VERSION 5.7 ;
  NOWIREEXTENSIONATPIN ON ;
  DIVIDERCHAR "/" ;
  BUSBITCHARS "[]" ;
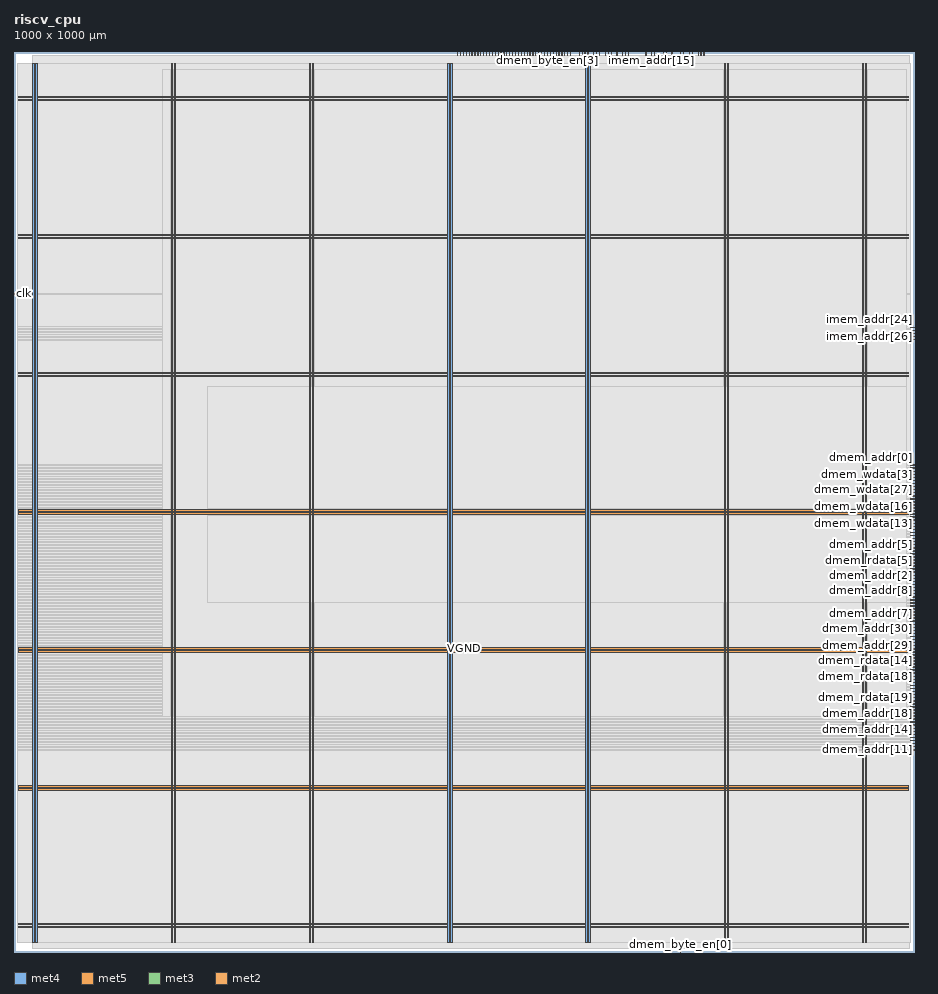
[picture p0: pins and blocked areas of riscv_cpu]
MACRO riscv_cpu
  CLASS BLOCK ;
  FOREIGN riscv_cpu ;
  ORIGIN 0.000 0.000 ;
  SIZE 1000.000 BY 1000.000 ;
  PIN VGND
    DIRECTION INOUT ;
    USE GROUND ;
    PORT
      LAYER met4 ;
        RECT 24.340 10.640 25.940 987.600 ;
    END
    PORT
      LAYER met4 ;
        RECT 177.940 10.640 179.540 987.600 ;
    END
    PORT
      LAYER met4 ;
        RECT 331.540 10.640 333.140 987.600 ;
    END
    PORT
      LAYER met4 ;
        RECT 485.140 10.640 486.740 987.600 ;
    END
    PORT
      LAYER met4 ;
        RECT 638.740 10.640 640.340 987.600 ;
    END
    PORT
      LAYER met4 ;
        RECT 792.340 10.640 793.940 987.600 ;
    END
    PORT
      LAYER met4 ;
        RECT 945.940 10.640 947.540 987.600 ;
    END
    PORT
      LAYER met5 ;
        RECT 5.280 30.030 994.300 31.630 ;
    END
    PORT
      LAYER met5 ;
        RECT 5.280 183.210 994.300 184.810 ;
    END
    PORT
      LAYER met5 ;
        RECT 5.280 336.390 994.300 337.990 ;
    END
    PORT
      LAYER met5 ;
        RECT 5.280 489.570 994.300 491.170 ;
    END
    PORT
      LAYER met5 ;
        RECT 5.280 642.750 994.300 644.350 ;
    END
    PORT
      LAYER met5 ;
        RECT 5.280 795.930 994.300 797.530 ;
    END
    PORT
      LAYER met5 ;
        RECT 5.280 949.110 994.300 950.710 ;
    END
  END VGND
  PIN VPWR
    DIRECTION INOUT ;
    USE POWER ;
    PORT
      LAYER met4 ;
        RECT 21.040 10.640 22.640 987.600 ;
    END
    PORT
      LAYER met4 ;
        RECT 174.640 10.640 176.240 987.600 ;
    END
    PORT
      LAYER met4 ;
        RECT 328.240 10.640 329.840 987.600 ;
    END
    PORT
      LAYER met4 ;
        RECT 481.840 10.640 483.440 987.600 ;
    END
    PORT
      LAYER met4 ;
        RECT 635.440 10.640 637.040 987.600 ;
    END
    PORT
      LAYER met4 ;
        RECT 789.040 10.640 790.640 987.600 ;
    END
    PORT
      LAYER met4 ;
        RECT 942.640 10.640 944.240 987.600 ;
    END
    PORT
      LAYER met5 ;
        RECT 5.280 26.730 994.300 28.330 ;
    END
    PORT
      LAYER met5 ;
        RECT 5.280 179.910 994.300 181.510 ;
    END
    PORT
      LAYER met5 ;
        RECT 5.280 333.090 994.300 334.690 ;
    END
    PORT
      LAYER met5 ;
        RECT 5.280 486.270 994.300 487.870 ;
    END
    PORT
      LAYER met5 ;
        RECT 5.280 639.450 994.300 641.050 ;
    END
    PORT
      LAYER met5 ;
        RECT 5.280 792.630 994.300 794.230 ;
    END
    PORT
      LAYER met5 ;
        RECT 5.280 945.810 994.300 947.410 ;
    END
  END VPWR
  PIN clk
    DIRECTION INPUT ;
    USE SIGNAL ;
    ANTENNAGATEAREA 0.852000 ;
    PORT
      LAYER met3 ;
        RECT 0.000 731.040 4.000 731.640 ;
    END
  END clk
  PIN dmem_addr[0]
    DIRECTION OUTPUT TRISTATE ;
    USE SIGNAL ;
    ANTENNADIFFAREA 0.445500 ;
    PORT
      LAYER met3 ;
        RECT 996.000 540.640 1000.000 541.240 ;
    END
  END dmem_addr[0]
  PIN dmem_addr[10]
    DIRECTION OUTPUT TRISTATE ;
    USE SIGNAL ;
    ANTENNADIFFAREA 0.445500 ;
    PORT
      LAYER met3 ;
        RECT 996.000 360.440 1000.000 361.040 ;
    END
  END dmem_addr[10]
  PIN dmem_addr[11]
    DIRECTION OUTPUT TRISTATE ;
    USE SIGNAL ;
    ANTENNADIFFAREA 0.795200 ;
    PORT
      LAYER met3 ;
        RECT 996.000 224.440 1000.000 225.040 ;
    END
  END dmem_addr[11]
  PIN dmem_addr[12]
    DIRECTION OUTPUT TRISTATE ;
    USE SIGNAL ;
    ANTENNADIFFAREA 0.445500 ;
    PORT
      LAYER met3 ;
        RECT 996.000 346.840 1000.000 347.440 ;
    END
  END dmem_addr[12]
  PIN dmem_addr[13]
    DIRECTION OUTPUT TRISTATE ;
    USE SIGNAL ;
    ANTENNADIFFAREA 0.795200 ;
    PORT
      LAYER met3 ;
        RECT 996.000 227.840 1000.000 228.440 ;
    END
  END dmem_addr[13]
  PIN dmem_addr[14]
    DIRECTION OUTPUT TRISTATE ;
    USE SIGNAL ;
    ANTENNADIFFAREA 0.445500 ;
    PORT
      LAYER met3 ;
        RECT 996.000 238.040 1000.000 238.640 ;
    END
  END dmem_addr[14]
  PIN dmem_addr[15]
    DIRECTION OUTPUT TRISTATE ;
    USE SIGNAL ;
    ANTENNADIFFAREA 0.795200 ;
    PORT
      LAYER met3 ;
        RECT 996.000 241.440 1000.000 242.040 ;
    END
  END dmem_addr[15]
  PIN dmem_addr[16]
    DIRECTION OUTPUT TRISTATE ;
    USE SIGNAL ;
    ANTENNADIFFAREA 0.795200 ;
    PORT
      LAYER met3 ;
        RECT 996.000 336.640 1000.000 337.240 ;
    END
  END dmem_addr[16]
  PIN dmem_addr[17]
    DIRECTION OUTPUT TRISTATE ;
    USE SIGNAL ;
    ANTENNADIFFAREA 0.445500 ;
    PORT
      LAYER met3 ;
        RECT 996.000 251.640 1000.000 252.240 ;
    END
  END dmem_addr[17]
  PIN dmem_addr[18]
    DIRECTION OUTPUT TRISTATE ;
    USE SIGNAL ;
    ANTENNADIFFAREA 0.445500 ;
    PORT
      LAYER met3 ;
        RECT 996.000 265.240 1000.000 265.840 ;
    END
  END dmem_addr[18]
  PIN dmem_addr[19]
    DIRECTION OUTPUT TRISTATE ;
    USE SIGNAL ;
    ANTENNADIFFAREA 0.795200 ;
    PORT
      LAYER met3 ;
        RECT 996.000 275.440 1000.000 276.040 ;
    END
  END dmem_addr[19]
  PIN dmem_addr[1]
    DIRECTION OUTPUT TRISTATE ;
    USE SIGNAL ;
    ANTENNADIFFAREA 0.445500 ;
    PORT
      LAYER met3 ;
        RECT 996.000 445.440 1000.000 446.040 ;
    END
  END dmem_addr[1]
  PIN dmem_addr[20]
    DIRECTION OUTPUT TRISTATE ;
    USE SIGNAL ;
    ANTENNADIFFAREA 0.795200 ;
    PORT
      LAYER met3 ;
        RECT 996.000 302.640 1000.000 303.240 ;
    END
  END dmem_addr[20]
  PIN dmem_addr[21]
    DIRECTION OUTPUT TRISTATE ;
    USE SIGNAL ;
    ANTENNADIFFAREA 0.795200 ;
    PORT
      LAYER met3 ;
        RECT 996.000 255.040 1000.000 255.640 ;
    END
  END dmem_addr[21]
  PIN dmem_addr[22]
    DIRECTION OUTPUT TRISTATE ;
    USE SIGNAL ;
    ANTENNADIFFAREA 0.445500 ;
    PORT
      LAYER met3 ;
        RECT 996.000 278.840 1000.000 279.440 ;
    END
  END dmem_addr[22]
  PIN dmem_addr[23]
    DIRECTION OUTPUT TRISTATE ;
    USE SIGNAL ;
    ANTENNADIFFAREA 0.795200 ;
    PORT
      LAYER met3 ;
        RECT 996.000 268.640 1000.000 269.240 ;
    END
  END dmem_addr[23]
  PIN dmem_addr[24]
    DIRECTION OUTPUT TRISTATE ;
    USE SIGNAL ;
    ANTENNADIFFAREA 0.445500 ;
    PORT
      LAYER met3 ;
        RECT 996.000 312.840 1000.000 313.440 ;
    END
  END dmem_addr[24]
  PIN dmem_addr[25]
    DIRECTION OUTPUT TRISTATE ;
    USE SIGNAL ;
    ANTENNADIFFAREA 0.445500 ;
    PORT
      LAYER met3 ;
        RECT 996.000 319.640 1000.000 320.240 ;
    END
  END dmem_addr[25]
  PIN dmem_addr[26]
    DIRECTION OUTPUT TRISTATE ;
    USE SIGNAL ;
    ANTENNADIFFAREA 0.795200 ;
    PORT
      LAYER met3 ;
        RECT 996.000 248.240 1000.000 248.840 ;
    END
  END dmem_addr[26]
  PIN dmem_addr[27]
    DIRECTION OUTPUT TRISTATE ;
    USE SIGNAL ;
    ANTENNADIFFAREA 0.445500 ;
    PORT
      LAYER met3 ;
        RECT 996.000 343.440 1000.000 344.040 ;
    END
  END dmem_addr[27]
  PIN dmem_addr[28]
    DIRECTION OUTPUT TRISTATE ;
    USE SIGNAL ;
    ANTENNADIFFAREA 0.795200 ;
    PORT
      LAYER met3 ;
        RECT 996.000 234.640 1000.000 235.240 ;
    END
  END dmem_addr[28]
  PIN dmem_addr[29]
    DIRECTION OUTPUT TRISTATE ;
    USE SIGNAL ;
    ANTENNADIFFAREA 0.445500 ;
    PORT
      LAYER met3 ;
        RECT 996.000 340.040 1000.000 340.640 ;
    END
  END dmem_addr[29]
  PIN dmem_addr[2]
    DIRECTION OUTPUT TRISTATE ;
    USE SIGNAL ;
    ANTENNADIFFAREA 0.445500 ;
    PORT
      LAYER met3 ;
        RECT 996.000 418.240 1000.000 418.840 ;
    END
  END dmem_addr[2]
  PIN dmem_addr[30]
    DIRECTION OUTPUT TRISTATE ;
    USE SIGNAL ;
    ANTENNADIFFAREA 0.795200 ;
    PORT
      LAYER met3 ;
        RECT 996.000 350.240 1000.000 350.840 ;
    END
  END dmem_addr[30]
  PIN dmem_addr[31]
    DIRECTION OUTPUT TRISTATE ;
    USE SIGNAL ;
    ANTENNADIFFAREA 0.445500 ;
    PORT
      LAYER met3 ;
        RECT 996.000 370.640 1000.000 371.240 ;
    END
  END dmem_addr[31]
  PIN dmem_addr[3]
    DIRECTION OUTPUT TRISTATE ;
    USE SIGNAL ;
    ANTENNADIFFAREA 0.445500 ;
    PORT
      LAYER met3 ;
        RECT 996.000 520.240 1000.000 520.840 ;
    END
  END dmem_addr[3]
  PIN dmem_addr[4]
    DIRECTION OUTPUT TRISTATE ;
    USE SIGNAL ;
    ANTENNADIFFAREA 0.795200 ;
    PORT
      LAYER met3 ;
        RECT 996.000 428.440 1000.000 429.040 ;
    END
  END dmem_addr[4]
  PIN dmem_addr[5]
    DIRECTION OUTPUT TRISTATE ;
    USE SIGNAL ;
    ANTENNADIFFAREA 0.445500 ;
    PORT
      LAYER met3 ;
        RECT 996.000 452.240 1000.000 452.840 ;
    END
  END dmem_addr[5]
  PIN dmem_addr[6]
    DIRECTION OUTPUT TRISTATE ;
    USE SIGNAL ;
    ANTENNADIFFAREA 0.795200 ;
    PORT
      LAYER met3 ;
        RECT 996.000 357.040 1000.000 357.640 ;
    END
  END dmem_addr[6]
  PIN dmem_addr[7]
    DIRECTION OUTPUT TRISTATE ;
    USE SIGNAL ;
    ANTENNADIFFAREA 0.445500 ;
    PORT
      LAYER met3 ;
        RECT 996.000 367.240 1000.000 367.840 ;
    END
  END dmem_addr[7]
  PIN dmem_addr[8]
    DIRECTION OUTPUT TRISTATE ;
    USE SIGNAL ;
    ANTENNADIFFAREA 0.445500 ;
    PORT
      LAYER met3 ;
        RECT 996.000 401.240 1000.000 401.840 ;
    END
  END dmem_addr[8]
  PIN dmem_addr[9]
    DIRECTION OUTPUT TRISTATE ;
    USE SIGNAL ;
    ANTENNADIFFAREA 0.795200 ;
    PORT
      LAYER met3 ;
        RECT 996.000 380.840 1000.000 381.440 ;
    END
  END dmem_addr[9]
  PIN dmem_byte_en[0]
    DIRECTION OUTPUT TRISTATE ;
    USE SIGNAL ;
    PORT
      LAYER met2 ;
        RECT 740.690 0.000 740.970 4.000 ;
    END
  END dmem_byte_en[0]
  PIN dmem_byte_en[1]
    DIRECTION OUTPUT TRISTATE ;
    USE SIGNAL ;
    ANTENNADIFFAREA 0.795200 ;
    PORT
      LAYER met2 ;
        RECT 608.670 996.000 608.950 1000.000 ;
    END
  END dmem_byte_en[1]
  PIN dmem_byte_en[2]
    DIRECTION OUTPUT TRISTATE ;
    USE SIGNAL ;
    ANTENNADIFFAREA 0.795200 ;
    PORT
      LAYER met2 ;
        RECT 582.910 996.000 583.190 1000.000 ;
    END
  END dmem_byte_en[2]
  PIN dmem_byte_en[3]
    DIRECTION OUTPUT TRISTATE ;
    USE SIGNAL ;
    ANTENNADIFFAREA 0.795200 ;
    PORT
      LAYER met2 ;
        RECT 592.570 996.000 592.850 1000.000 ;
    END
  END dmem_byte_en[3]
  PIN dmem_rdata[0]
    DIRECTION INPUT ;
    USE SIGNAL ;
    ANTENNAGATEAREA 0.213000 ;
    PORT
      LAYER met3 ;
        RECT 996.000 462.440 1000.000 463.040 ;
    END
  END dmem_rdata[0]
  PIN dmem_rdata[10]
    DIRECTION INPUT ;
    USE SIGNAL ;
    ANTENNAGATEAREA 0.213000 ;
    PORT
      LAYER met3 ;
        RECT 996.000 374.040 1000.000 374.640 ;
    END
  END dmem_rdata[10]
  PIN dmem_rdata[11]
    DIRECTION INPUT ;
    USE SIGNAL ;
    ANTENNAGATEAREA 0.213000 ;
    PORT
      LAYER met3 ;
        RECT 996.000 363.840 1000.000 364.440 ;
    END
  END dmem_rdata[11]
  PIN dmem_rdata[12]
    DIRECTION INPUT ;
    USE SIGNAL ;
    ANTENNAGATEAREA 0.213000 ;
    PORT
      LAYER met3 ;
        RECT 996.000 353.640 1000.000 354.240 ;
    END
  END dmem_rdata[12]
  PIN dmem_rdata[13]
    DIRECTION INPUT ;
    USE SIGNAL ;
    ANTENNAGATEAREA 0.213000 ;
    PORT
      LAYER met3 ;
        RECT 996.000 261.840 1000.000 262.440 ;
    END
  END dmem_rdata[13]
  PIN dmem_rdata[14]
    DIRECTION INPUT ;
    USE SIGNAL ;
    ANTENNAGATEAREA 0.213000 ;
    PORT
      LAYER met3 ;
        RECT 996.000 323.040 1000.000 323.640 ;
    END
  END dmem_rdata[14]
  PIN dmem_rdata[15]
    DIRECTION INPUT ;
    USE SIGNAL ;
    ANTENNAGATEAREA 0.213000 ;
    PORT
      LAYER met3 ;
        RECT 996.000 309.440 1000.000 310.040 ;
    END
  END dmem_rdata[15]
  PIN dmem_rdata[16]
    DIRECTION INPUT ;
    USE SIGNAL ;
    ANTENNAGATEAREA 0.213000 ;
    PORT
      LAYER met3 ;
        RECT 996.000 244.840 1000.000 245.440 ;
    END
  END dmem_rdata[16]
  PIN dmem_rdata[17]
    DIRECTION INPUT ;
    USE SIGNAL ;
    ANTENNAGATEAREA 0.213000 ;
    PORT
      LAYER met3 ;
        RECT 996.000 272.040 1000.000 272.640 ;
    END
  END dmem_rdata[17]
  PIN dmem_rdata[18]
    DIRECTION INPUT ;
    USE SIGNAL ;
    ANTENNAGATEAREA 0.213000 ;
    PORT
      LAYER met3 ;
        RECT 996.000 306.040 1000.000 306.640 ;
    END
  END dmem_rdata[18]
  PIN dmem_rdata[19]
    DIRECTION INPUT ;
    USE SIGNAL ;
    ANTENNAGATEAREA 0.159000 ;
    PORT
      LAYER met3 ;
        RECT 996.000 282.240 1000.000 282.840 ;
    END
  END dmem_rdata[19]
  PIN dmem_rdata[1]
    DIRECTION INPUT ;
    USE SIGNAL ;
    ANTENNAGATEAREA 0.213000 ;
    PORT
      LAYER met3 ;
        RECT 996.000 421.640 1000.000 422.240 ;
    END
  END dmem_rdata[1]
  PIN dmem_rdata[20]
    DIRECTION INPUT ;
    USE SIGNAL ;
    ANTENNAGATEAREA 0.213000 ;
    PORT
      LAYER met3 ;
        RECT 996.000 285.640 1000.000 286.240 ;
    END
  END dmem_rdata[20]
  PIN dmem_rdata[21]
    DIRECTION INPUT ;
    USE SIGNAL ;
    ANTENNAGATEAREA 0.159000 ;
    PORT
      LAYER met3 ;
        RECT 996.000 299.240 1000.000 299.840 ;
    END
  END dmem_rdata[21]
  PIN dmem_rdata[22]
    DIRECTION INPUT ;
    USE SIGNAL ;
    ANTENNAGATEAREA 0.159000 ;
    PORT
      LAYER met3 ;
        RECT 996.000 292.440 1000.000 293.040 ;
    END
  END dmem_rdata[22]
  PIN dmem_rdata[23]
    DIRECTION INPUT ;
    USE SIGNAL ;
    ANTENNAGATEAREA 0.213000 ;
    PORT
      LAYER met3 ;
        RECT 996.000 289.040 1000.000 289.640 ;
    END
  END dmem_rdata[23]
  PIN dmem_rdata[24]
    DIRECTION INPUT ;
    USE SIGNAL ;
    ANTENNAGATEAREA 0.213000 ;
    PORT
      LAYER met3 ;
        RECT 996.000 295.840 1000.000 296.440 ;
    END
  END dmem_rdata[24]
  PIN dmem_rdata[25]
    DIRECTION INPUT ;
    USE SIGNAL ;
    ANTENNAGATEAREA 0.213000 ;
    PORT
      LAYER met3 ;
        RECT 996.000 316.240 1000.000 316.840 ;
    END
  END dmem_rdata[25]
  PIN dmem_rdata[26]
    DIRECTION INPUT ;
    USE SIGNAL ;
    ANTENNAGATEAREA 0.213000 ;
    PORT
      LAYER met3 ;
        RECT 996.000 258.440 1000.000 259.040 ;
    END
  END dmem_rdata[26]
  PIN dmem_rdata[27]
    DIRECTION INPUT ;
    USE SIGNAL ;
    ANTENNAGATEAREA 0.213000 ;
    PORT
      LAYER met3 ;
        RECT 996.000 333.240 1000.000 333.840 ;
    END
  END dmem_rdata[27]
  PIN dmem_rdata[28]
    DIRECTION INPUT ;
    USE SIGNAL ;
    ANTENNAGATEAREA 0.213000 ;
    PORT
      LAYER met3 ;
        RECT 996.000 326.440 1000.000 327.040 ;
    END
  END dmem_rdata[28]
  PIN dmem_rdata[29]
    DIRECTION INPUT ;
    USE SIGNAL ;
    ANTENNAGATEAREA 0.213000 ;
    PORT
      LAYER met3 ;
        RECT 996.000 231.240 1000.000 231.840 ;
    END
  END dmem_rdata[29]
  PIN dmem_rdata[2]
    DIRECTION INPUT ;
    USE SIGNAL ;
    ANTENNAGATEAREA 0.213000 ;
    PORT
      LAYER met3 ;
        RECT 996.000 425.040 1000.000 425.640 ;
    END
  END dmem_rdata[2]
  PIN dmem_rdata[30]
    DIRECTION INPUT ;
    USE SIGNAL ;
    ANTENNAGATEAREA 0.213000 ;
    PORT
      LAYER met3 ;
        RECT 996.000 329.840 1000.000 330.440 ;
    END
  END dmem_rdata[30]
  PIN dmem_rdata[31]
    DIRECTION INPUT ;
    USE SIGNAL ;
    ANTENNAGATEAREA 0.213000 ;
    PORT
      LAYER met3 ;
        RECT 996.000 459.040 1000.000 459.640 ;
    END
  END dmem_rdata[31]
  PIN dmem_rdata[3]
    DIRECTION INPUT ;
    USE SIGNAL ;
    ANTENNAGATEAREA 0.213000 ;
    PORT
      LAYER met3 ;
        RECT 996.000 438.640 1000.000 439.240 ;
    END
  END dmem_rdata[3]
  PIN dmem_rdata[4]
    DIRECTION INPUT ;
    USE SIGNAL ;
    ANTENNAGATEAREA 0.213000 ;
    PORT
      LAYER met3 ;
        RECT 996.000 506.640 1000.000 507.240 ;
    END
  END dmem_rdata[4]
  PIN dmem_rdata[5]
    DIRECTION INPUT ;
    USE SIGNAL ;
    ANTENNAGATEAREA 0.213000 ;
    PORT
      LAYER met3 ;
        RECT 996.000 435.240 1000.000 435.840 ;
    END
  END dmem_rdata[5]
  PIN dmem_rdata[6]
    DIRECTION INPUT ;
    USE SIGNAL ;
    ANTENNAGATEAREA 0.213000 ;
    PORT
      LAYER met3 ;
        RECT 996.000 411.440 1000.000 412.040 ;
    END
  END dmem_rdata[6]
  PIN dmem_rdata[7]
    DIRECTION INPUT ;
    USE SIGNAL ;
    ANTENNAGATEAREA 0.213000 ;
    PORT
      LAYER met3 ;
        RECT 996.000 377.440 1000.000 378.040 ;
    END
  END dmem_rdata[7]
  PIN dmem_rdata[8]
    DIRECTION INPUT ;
    USE SIGNAL ;
    ANTENNAGATEAREA 0.213000 ;
    PORT
      LAYER met3 ;
        RECT 996.000 387.640 1000.000 388.240 ;
    END
  END dmem_rdata[8]
  PIN dmem_rdata[9]
    DIRECTION INPUT ;
    USE SIGNAL ;
    ANTENNAGATEAREA 0.213000 ;
    PORT
      LAYER met3 ;
        RECT 996.000 384.240 1000.000 384.840 ;
    END
  END dmem_rdata[9]
  PIN dmem_re
    DIRECTION OUTPUT TRISTATE ;
    USE SIGNAL ;
    ANTENNADIFFAREA 0.795200 ;
    PORT
      LAYER met2 ;
        RECT 566.810 996.000 567.090 1000.000 ;
    END
  END dmem_re
  PIN dmem_wdata[0]
    DIRECTION OUTPUT TRISTATE ;
    USE SIGNAL ;
    ANTENNADIFFAREA 0.795200 ;
    PORT
      LAYER met3 ;
        RECT 996.000 516.840 1000.000 517.440 ;
    END
  END dmem_wdata[0]
  PIN dmem_wdata[10]
    DIRECTION OUTPUT TRISTATE ;
    USE SIGNAL ;
    ANTENNADIFFAREA 0.795200 ;
    PORT
      LAYER met3 ;
        RECT 996.000 408.040 1000.000 408.640 ;
    END
  END dmem_wdata[10]
  PIN dmem_wdata[11]
    DIRECTION OUTPUT TRISTATE ;
    USE SIGNAL ;
    ANTENNADIFFAREA 0.445500 ;
    PORT
      LAYER met3 ;
        RECT 996.000 472.640 1000.000 473.240 ;
    END
  END dmem_wdata[11]
  PIN dmem_wdata[12]
    DIRECTION OUTPUT TRISTATE ;
    USE SIGNAL ;
    ANTENNADIFFAREA 0.445500 ;
    PORT
      LAYER met3 ;
        RECT 996.000 391.040 1000.000 391.640 ;
    END
  END dmem_wdata[12]
  PIN dmem_wdata[13]
    DIRECTION OUTPUT TRISTATE ;
    USE SIGNAL ;
    ANTENNADIFFAREA 0.795200 ;
    PORT
      LAYER met3 ;
        RECT 996.000 476.040 1000.000 476.640 ;
    END
  END dmem_wdata[13]
  PIN dmem_wdata[14]
    DIRECTION OUTPUT TRISTATE ;
    USE SIGNAL ;
    ANTENNADIFFAREA 0.795200 ;
    PORT
      LAYER met3 ;
        RECT 996.000 404.640 1000.000 405.240 ;
    END
  END dmem_wdata[14]
  PIN dmem_wdata[15]
    DIRECTION OUTPUT TRISTATE ;
    USE SIGNAL ;
    ANTENNADIFFAREA 0.445500 ;
    PORT
      LAYER met3 ;
        RECT 996.000 394.440 1000.000 395.040 ;
    END
  END dmem_wdata[15]
  PIN dmem_wdata[16]
    DIRECTION OUTPUT TRISTATE ;
    USE SIGNAL ;
    ANTENNADIFFAREA 0.445500 ;
    PORT
      LAYER met3 ;
        RECT 996.000 486.240 1000.000 486.840 ;
    END
  END dmem_wdata[16]
  PIN dmem_wdata[17]
    DIRECTION OUTPUT TRISTATE ;
    USE SIGNAL ;
    ANTENNADIFFAREA 0.445500 ;
    PORT
      LAYER met3 ;
        RECT 996.000 527.040 1000.000 527.640 ;
    END
  END dmem_wdata[17]
  PIN dmem_wdata[18]
    DIRECTION OUTPUT TRISTATE ;
    USE SIGNAL ;
    ANTENNADIFFAREA 0.795200 ;
    PORT
      LAYER met3 ;
        RECT 996.000 455.640 1000.000 456.240 ;
    END
  END dmem_wdata[18]
  PIN dmem_wdata[19]
    DIRECTION OUTPUT TRISTATE ;
    USE SIGNAL ;
    ANTENNADIFFAREA 0.795200 ;
    PORT
      LAYER met3 ;
        RECT 996.000 510.040 1000.000 510.640 ;
    END
  END dmem_wdata[19]
  PIN dmem_wdata[1]
    DIRECTION OUTPUT TRISTATE ;
    USE SIGNAL ;
    ANTENNADIFFAREA 0.795200 ;
    PORT
      LAYER met3 ;
        RECT 996.000 496.440 1000.000 497.040 ;
    END
  END dmem_wdata[1]
  PIN dmem_wdata[20]
    DIRECTION OUTPUT TRISTATE ;
    USE SIGNAL ;
    ANTENNADIFFAREA 0.795200 ;
    PORT
      LAYER met3 ;
        RECT 996.000 448.840 1000.000 449.440 ;
    END
  END dmem_wdata[20]
  PIN dmem_wdata[21]
    DIRECTION OUTPUT TRISTATE ;
    USE SIGNAL ;
    ANTENNADIFFAREA 0.795200 ;
    PORT
      LAYER met3 ;
        RECT 996.000 482.840 1000.000 483.440 ;
    END
  END dmem_wdata[21]
  PIN dmem_wdata[22]
    DIRECTION OUTPUT TRISTATE ;
    USE SIGNAL ;
    ANTENNADIFFAREA 0.445500 ;
    PORT
      LAYER met3 ;
        RECT 996.000 499.840 1000.000 500.440 ;
    END
  END dmem_wdata[22]
  PIN dmem_wdata[23]
    DIRECTION OUTPUT TRISTATE ;
    USE SIGNAL ;
    ANTENNADIFFAREA 0.445500 ;
    PORT
      LAYER met3 ;
        RECT 996.000 465.840 1000.000 466.440 ;
    END
  END dmem_wdata[23]
  PIN dmem_wdata[24]
    DIRECTION OUTPUT TRISTATE ;
    USE SIGNAL ;
    ANTENNADIFFAREA 0.445500 ;
    PORT
      LAYER met3 ;
        RECT 996.000 442.040 1000.000 442.640 ;
    END
  END dmem_wdata[24]
  PIN dmem_wdata[25]
    DIRECTION OUTPUT TRISTATE ;
    USE SIGNAL ;
    ANTENNADIFFAREA 0.445500 ;
    PORT
      LAYER met3 ;
        RECT 996.000 469.240 1000.000 469.840 ;
    END
  END dmem_wdata[25]
  PIN dmem_wdata[26]
    DIRECTION OUTPUT TRISTATE ;
    USE SIGNAL ;
    ANTENNADIFFAREA 0.795200 ;
    PORT
      LAYER met3 ;
        RECT 996.000 537.240 1000.000 537.840 ;
    END
  END dmem_wdata[26]
  PIN dmem_wdata[27]
    DIRECTION OUTPUT TRISTATE ;
    USE SIGNAL ;
    ANTENNADIFFAREA 0.445500 ;
    PORT
      LAYER met3 ;
        RECT 996.000 513.440 1000.000 514.040 ;
    END
  END dmem_wdata[27]
  PIN dmem_wdata[28]
    DIRECTION OUTPUT TRISTATE ;
    USE SIGNAL ;
    ANTENNADIFFAREA 0.445500 ;
    PORT
      LAYER met3 ;
        RECT 996.000 493.040 1000.000 493.640 ;
    END
  END dmem_wdata[28]
  PIN dmem_wdata[29]
    DIRECTION OUTPUT TRISTATE ;
    USE SIGNAL ;
    ANTENNADIFFAREA 0.795200 ;
    PORT
      LAYER met3 ;
        RECT 996.000 489.640 1000.000 490.240 ;
    END
  END dmem_wdata[29]
  PIN dmem_wdata[2]
    DIRECTION OUTPUT TRISTATE ;
    USE SIGNAL ;
    ANTENNADIFFAREA 0.445500 ;
    PORT
      LAYER met3 ;
        RECT 996.000 479.440 1000.000 480.040 ;
    END
  END dmem_wdata[2]
  PIN dmem_wdata[30]
    DIRECTION OUTPUT TRISTATE ;
    USE SIGNAL ;
    ANTENNADIFFAREA 0.795200 ;
    PORT
      LAYER met3 ;
        RECT 996.000 523.640 1000.000 524.240 ;
    END
  END dmem_wdata[30]
  PIN dmem_wdata[31]
    DIRECTION OUTPUT TRISTATE ;
    USE SIGNAL ;
    ANTENNADIFFAREA 0.445500 ;
    PORT
      LAYER met3 ;
        RECT 996.000 533.840 1000.000 534.440 ;
    END
  END dmem_wdata[31]
  PIN dmem_wdata[3]
    DIRECTION OUTPUT TRISTATE ;
    USE SIGNAL ;
    ANTENNADIFFAREA 0.795200 ;
    PORT
      LAYER met3 ;
        RECT 996.000 530.440 1000.000 531.040 ;
    END
  END dmem_wdata[3]
  PIN dmem_wdata[4]
    DIRECTION OUTPUT TRISTATE ;
    USE SIGNAL ;
    ANTENNADIFFAREA 0.445500 ;
    PORT
      LAYER met3 ;
        RECT 996.000 414.840 1000.000 415.440 ;
    END
  END dmem_wdata[4]
  PIN dmem_wdata[5]
    DIRECTION OUTPUT TRISTATE ;
    USE SIGNAL ;
    ANTENNADIFFAREA 0.795200 ;
    PORT
      LAYER met2 ;
        RECT 615.110 996.000 615.390 1000.000 ;
    END
  END dmem_wdata[5]
  PIN dmem_wdata[6]
    DIRECTION OUTPUT TRISTATE ;
    USE SIGNAL ;
    ANTENNADIFFAREA 0.795200 ;
    PORT
      LAYER met2 ;
        RECT 611.890 996.000 612.170 1000.000 ;
    END
  END dmem_wdata[6]
  PIN dmem_wdata[7]
    DIRECTION OUTPUT TRISTATE ;
    USE SIGNAL ;
    ANTENNADIFFAREA 0.795200 ;
    PORT
      LAYER met2 ;
        RECT 618.330 996.000 618.610 1000.000 ;
    END
  END dmem_wdata[7]
  PIN dmem_wdata[8]
    DIRECTION OUTPUT TRISTATE ;
    USE SIGNAL ;
    ANTENNADIFFAREA 0.445500 ;
    PORT
      LAYER met3 ;
        RECT 996.000 397.840 1000.000 398.440 ;
    END
  END dmem_wdata[8]
  PIN dmem_wdata[9]
    DIRECTION OUTPUT TRISTATE ;
    USE SIGNAL ;
    ANTENNADIFFAREA 0.795200 ;
    PORT
      LAYER met3 ;
        RECT 996.000 503.240 1000.000 503.840 ;
    END
  END dmem_wdata[9]
  PIN dmem_we
    DIRECTION OUTPUT TRISTATE ;
    USE SIGNAL ;
    ANTENNADIFFAREA 0.795200 ;
    PORT
      LAYER met2 ;
        RECT 586.130 996.000 586.410 1000.000 ;
    END
  END dmem_we
  PIN imem_addr[0]
    DIRECTION OUTPUT TRISTATE ;
    USE SIGNAL ;
    ANTENNADIFFAREA 0.795200 ;
    PORT
      LAYER met2 ;
        RECT 656.970 996.000 657.250 1000.000 ;
    END
  END imem_addr[0]
  PIN imem_addr[10]
    DIRECTION OUTPUT TRISTATE ;
    USE SIGNAL ;
    ANTENNADIFFAREA 0.795200 ;
    PORT
      LAYER met2 ;
        RECT 663.410 996.000 663.690 1000.000 ;
    END
  END imem_addr[10]
  PIN imem_addr[11]
    DIRECTION OUTPUT TRISTATE ;
    USE SIGNAL ;
    ANTENNADIFFAREA 0.795200 ;
    PORT
      LAYER met2 ;
        RECT 676.290 996.000 676.570 1000.000 ;
    END
  END imem_addr[11]
  PIN imem_addr[12]
    DIRECTION OUTPUT TRISTATE ;
    USE SIGNAL ;
    ANTENNADIFFAREA 0.795200 ;
    PORT
      LAYER met2 ;
        RECT 679.510 996.000 679.790 1000.000 ;
    END
  END imem_addr[12]
  PIN imem_addr[13]
    DIRECTION OUTPUT TRISTATE ;
    USE SIGNAL ;
    ANTENNADIFFAREA 0.795200 ;
    PORT
      LAYER met2 ;
        RECT 682.730 996.000 683.010 1000.000 ;
    END
  END imem_addr[13]
  PIN imem_addr[14]
    DIRECTION OUTPUT TRISTATE ;
    USE SIGNAL ;
    ANTENNADIFFAREA 0.795200 ;
    PORT
      LAYER met2 ;
        RECT 702.050 996.000 702.330 1000.000 ;
    END
  END imem_addr[14]
  PIN imem_addr[15]
    DIRECTION OUTPUT TRISTATE ;
    USE SIGNAL ;
    ANTENNADIFFAREA 0.795200 ;
    PORT
      LAYER met2 ;
        RECT 708.490 996.000 708.770 1000.000 ;
    END
  END imem_addr[15]
  PIN imem_addr[16]
    DIRECTION OUTPUT TRISTATE ;
    USE SIGNAL ;
    ANTENNADIFFAREA 0.795200 ;
    PORT
      LAYER met2 ;
        RECT 711.710 996.000 711.990 1000.000 ;
    END
  END imem_addr[16]
  PIN imem_addr[17]
    DIRECTION OUTPUT TRISTATE ;
    USE SIGNAL ;
    ANTENNADIFFAREA 0.795200 ;
    PORT
      LAYER met2 ;
        RECT 724.590 996.000 724.870 1000.000 ;
    END
  END imem_addr[17]
  PIN imem_addr[18]
    DIRECTION OUTPUT TRISTATE ;
    USE SIGNAL ;
    ANTENNADIFFAREA 0.795200 ;
    PORT
      LAYER met2 ;
        RECT 721.370 996.000 721.650 1000.000 ;
    END
  END imem_addr[18]
  PIN imem_addr[19]
    DIRECTION OUTPUT TRISTATE ;
    USE SIGNAL ;
    ANTENNADIFFAREA 0.795200 ;
    PORT
      LAYER met2 ;
        RECT 731.030 996.000 731.310 1000.000 ;
    END
  END imem_addr[19]
  PIN imem_addr[1]
    DIRECTION OUTPUT TRISTATE ;
    USE SIGNAL ;
    ANTENNADIFFAREA 0.795200 ;
    PORT
      LAYER met2 ;
        RECT 669.850 996.000 670.130 1000.000 ;
    END
  END imem_addr[1]
  PIN imem_addr[20]
    DIRECTION OUTPUT TRISTATE ;
    USE SIGNAL ;
    ANTENNADIFFAREA 0.795200 ;
    PORT
      LAYER met2 ;
        RECT 743.910 996.000 744.190 1000.000 ;
    END
  END imem_addr[20]
  PIN imem_addr[21]
    DIRECTION OUTPUT TRISTATE ;
    USE SIGNAL ;
    ANTENNADIFFAREA 0.795200 ;
    PORT
      LAYER met2 ;
        RECT 740.690 996.000 740.970 1000.000 ;
    END
  END imem_addr[21]
  PIN imem_addr[22]
    DIRECTION OUTPUT TRISTATE ;
    USE SIGNAL ;
    ANTENNADIFFAREA 0.795200 ;
    PORT
      LAYER met2 ;
        RECT 760.010 996.000 760.290 1000.000 ;
    END
  END imem_addr[22]
  PIN imem_addr[23]
    DIRECTION OUTPUT TRISTATE ;
    USE SIGNAL ;
    ANTENNADIFFAREA 0.795200 ;
    PORT
      LAYER met2 ;
        RECT 763.230 996.000 763.510 1000.000 ;
    END
  END imem_addr[23]
  PIN imem_addr[24]
    DIRECTION OUTPUT TRISTATE ;
    USE SIGNAL ;
    ANTENNADIFFAREA 0.445500 ;
    PORT
      LAYER met3 ;
        RECT 996.000 693.640 1000.000 694.240 ;
    END
  END imem_addr[24]
  PIN imem_addr[25]
    DIRECTION OUTPUT TRISTATE ;
    USE SIGNAL ;
    ANTENNADIFFAREA 0.795200 ;
    PORT
      LAYER met3 ;
        RECT 996.000 686.840 1000.000 687.440 ;
    END
  END imem_addr[25]
  PIN imem_addr[26]
    DIRECTION OUTPUT TRISTATE ;
    USE SIGNAL ;
    ANTENNADIFFAREA 0.795200 ;
    PORT
      LAYER met3 ;
        RECT 996.000 683.440 1000.000 684.040 ;
    END
  END imem_addr[26]
  PIN imem_addr[27]
    DIRECTION OUTPUT TRISTATE ;
    USE SIGNAL ;
    ANTENNADIFFAREA 0.795200 ;
    PORT
      LAYER met2 ;
        RECT 753.570 996.000 753.850 1000.000 ;
    END
  END imem_addr[27]
  PIN imem_addr[28]
    DIRECTION OUTPUT TRISTATE ;
    USE SIGNAL ;
    ANTENNADIFFAREA 0.795200 ;
    PORT
      LAYER met2 ;
        RECT 766.450 996.000 766.730 1000.000 ;
    END
  END imem_addr[28]
  PIN imem_addr[29]
    DIRECTION OUTPUT TRISTATE ;
    USE SIGNAL ;
    ANTENNADIFFAREA 0.795200 ;
    PORT
      LAYER met3 ;
        RECT 996.000 690.240 1000.000 690.840 ;
    END
  END imem_addr[29]
  PIN imem_addr[2]
    DIRECTION OUTPUT TRISTATE ;
    USE SIGNAL ;
    ANTENNADIFFAREA 0.795200 ;
    PORT
      LAYER met2 ;
        RECT 634.430 996.000 634.710 1000.000 ;
    END
  END imem_addr[2]
  PIN imem_addr[30]
    DIRECTION OUTPUT TRISTATE ;
    USE SIGNAL ;
    ANTENNADIFFAREA 0.795200 ;
    PORT
      LAYER met2 ;
        RECT 750.350 996.000 750.630 1000.000 ;
    END
  END imem_addr[30]
  PIN imem_addr[31]
    DIRECTION OUTPUT TRISTATE ;
    USE SIGNAL ;
    ANTENNADIFFAREA 0.445500 ;
    PORT
      LAYER met3 ;
        RECT 996.000 680.040 1000.000 680.640 ;
    END
  END imem_addr[31]
  PIN imem_addr[3]
    DIRECTION OUTPUT TRISTATE ;
    USE SIGNAL ;
    ANTENNADIFFAREA 0.795200 ;
    PORT
      LAYER met2 ;
        RECT 631.210 996.000 631.490 1000.000 ;
    END
  END imem_addr[3]
  PIN imem_addr[4]
    DIRECTION OUTPUT TRISTATE ;
    USE SIGNAL ;
    ANTENNADIFFAREA 0.795200 ;
    PORT
      LAYER met2 ;
        RECT 650.530 996.000 650.810 1000.000 ;
    END
  END imem_addr[4]
  PIN imem_addr[5]
    DIRECTION OUTPUT TRISTATE ;
    USE SIGNAL ;
    ANTENNADIFFAREA 0.795200 ;
    PORT
      LAYER met2 ;
        RECT 627.990 996.000 628.270 1000.000 ;
    END
  END imem_addr[5]
  PIN imem_addr[6]
    DIRECTION OUTPUT TRISTATE ;
    USE SIGNAL ;
    ANTENNADIFFAREA 0.795200 ;
    PORT
      LAYER met2 ;
        RECT 637.650 996.000 637.930 1000.000 ;
    END
  END imem_addr[6]
  PIN imem_addr[7]
    DIRECTION OUTPUT TRISTATE ;
    USE SIGNAL ;
    ANTENNADIFFAREA 0.795200 ;
    PORT
      LAYER met2 ;
        RECT 647.310 996.000 647.590 1000.000 ;
    END
  END imem_addr[7]
  PIN imem_addr[8]
    DIRECTION OUTPUT TRISTATE ;
    USE SIGNAL ;
    ANTENNADIFFAREA 0.795200 ;
    PORT
      LAYER met2 ;
        RECT 644.090 996.000 644.370 1000.000 ;
    END
  END imem_addr[8]
  PIN imem_addr[9]
    DIRECTION OUTPUT TRISTATE ;
    USE SIGNAL ;
    ANTENNADIFFAREA 0.795200 ;
    PORT
      LAYER met2 ;
        RECT 660.190 996.000 660.470 1000.000 ;
    END
  END imem_addr[9]
  PIN imem_data[0]
    DIRECTION INPUT ;
    USE SIGNAL ;
    ANTENNAGATEAREA 0.159000 ;
    PORT
      LAYER met2 ;
        RECT 570.030 996.000 570.310 1000.000 ;
    END
  END imem_data[0]
  PIN imem_data[10]
    DIRECTION INPUT ;
    USE SIGNAL ;
    ANTENNAGATEAREA 0.159000 ;
    PORT
      LAYER met2 ;
        RECT 528.170 996.000 528.450 1000.000 ;
    END
  END imem_data[10]
  PIN imem_data[11]
    DIRECTION INPUT ;
    USE SIGNAL ;
    ANTENNAGATEAREA 0.159000 ;
    PORT
      LAYER met2 ;
        RECT 531.390 996.000 531.670 1000.000 ;
    END
  END imem_data[11]
  PIN imem_data[12]
    DIRECTION INPUT ;
    USE SIGNAL ;
    ANTENNAGATEAREA 0.159000 ;
    PORT
      LAYER met2 ;
        RECT 537.830 996.000 538.110 1000.000 ;
    END
  END imem_data[12]
  PIN imem_data[13]
    DIRECTION INPUT ;
    USE SIGNAL ;
    ANTENNAGATEAREA 0.159000 ;
    PORT
      LAYER met2 ;
        RECT 492.750 996.000 493.030 1000.000 ;
    END
  END imem_data[13]
  PIN imem_data[14]
    DIRECTION INPUT ;
    USE SIGNAL ;
    ANTENNAGATEAREA 0.159000 ;
    PORT
      LAYER met2 ;
        RECT 534.610 996.000 534.890 1000.000 ;
    END
  END imem_data[14]
  PIN imem_data[15]
    DIRECTION INPUT ;
    USE SIGNAL ;
    ANTENNAGATEAREA 0.159000 ;
    PORT
      LAYER met2 ;
        RECT 495.970 996.000 496.250 1000.000 ;
    END
  END imem_data[15]
  PIN imem_data[16]
    DIRECTION INPUT ;
    USE SIGNAL ;
    ANTENNAGATEAREA 0.159000 ;
    PORT
      LAYER met2 ;
        RECT 505.630 996.000 505.910 1000.000 ;
    END
  END imem_data[16]
  PIN imem_data[17]
    DIRECTION INPUT ;
    USE SIGNAL ;
    ANTENNAGATEAREA 0.213000 ;
    PORT
      LAYER met2 ;
        RECT 499.190 996.000 499.470 1000.000 ;
    END
  END imem_data[17]
  PIN imem_data[18]
    DIRECTION INPUT ;
    USE SIGNAL ;
    ANTENNAGATEAREA 0.213000 ;
    PORT
      LAYER met2 ;
        RECT 502.410 996.000 502.690 1000.000 ;
    END
  END imem_data[18]
  PIN imem_data[19]
    DIRECTION INPUT ;
    USE SIGNAL ;
    ANTENNAGATEAREA 0.159000 ;
    PORT
      LAYER met2 ;
        RECT 512.070 996.000 512.350 1000.000 ;
    END
  END imem_data[19]
  PIN imem_data[1]
    DIRECTION INPUT ;
    USE SIGNAL ;
    ANTENNAGATEAREA 0.159000 ;
    PORT
      LAYER met2 ;
        RECT 573.250 996.000 573.530 1000.000 ;
    END
  END imem_data[1]
  PIN imem_data[20]
    DIRECTION INPUT ;
    USE SIGNAL ;
    ANTENNAGATEAREA 0.159000 ;
    PORT
      LAYER met2 ;
        RECT 515.290 996.000 515.570 1000.000 ;
    END
  END imem_data[20]
  PIN imem_data[21]
    DIRECTION INPUT ;
    USE SIGNAL ;
    ANTENNAGATEAREA 0.159000 ;
    PORT
      LAYER met2 ;
        RECT 508.850 996.000 509.130 1000.000 ;
    END
  END imem_data[21]
  PIN imem_data[22]
    DIRECTION INPUT ;
    USE SIGNAL ;
    ANTENNAGATEAREA 0.159000 ;
    PORT
      LAYER met2 ;
        RECT 521.730 996.000 522.010 1000.000 ;
    END
  END imem_data[22]
  PIN imem_data[23]
    DIRECTION INPUT ;
    USE SIGNAL ;
    ANTENNAGATEAREA 0.159000 ;
    PORT
      LAYER met2 ;
        RECT 524.950 996.000 525.230 1000.000 ;
    END
  END imem_data[23]
  PIN imem_data[24]
    DIRECTION INPUT ;
    USE SIGNAL ;
    ANTENNAGATEAREA 0.159000 ;
    PORT
      LAYER met2 ;
        RECT 518.510 996.000 518.790 1000.000 ;
    END
  END imem_data[24]
  PIN imem_data[25]
    DIRECTION INPUT ;
    USE SIGNAL ;
    ANTENNAGATEAREA 0.159000 ;
    PORT
      LAYER met2 ;
        RECT 550.710 996.000 550.990 1000.000 ;
    END
  END imem_data[25]
  PIN imem_data[26]
    DIRECTION INPUT ;
    USE SIGNAL ;
    ANTENNAGATEAREA 0.159000 ;
    PORT
      LAYER met2 ;
        RECT 605.450 996.000 605.730 1000.000 ;
    END
  END imem_data[26]
  PIN imem_data[27]
    DIRECTION INPUT ;
    USE SIGNAL ;
    ANTENNAGATEAREA 0.159000 ;
    PORT
      LAYER met2 ;
        RECT 602.230 996.000 602.510 1000.000 ;
    END
  END imem_data[27]
  PIN imem_data[28]
    DIRECTION INPUT ;
    USE SIGNAL ;
    ANTENNAGATEAREA 0.159000 ;
    PORT
      LAYER met2 ;
        RECT 595.790 996.000 596.070 1000.000 ;
    END
  END imem_data[28]
  PIN imem_data[29]
    DIRECTION INPUT ;
    USE SIGNAL ;
    ANTENNAGATEAREA 0.159000 ;
    PORT
      LAYER met2 ;
        RECT 599.010 996.000 599.290 1000.000 ;
    END
  END imem_data[29]
  PIN imem_data[2]
    DIRECTION INPUT ;
    USE SIGNAL ;
    ANTENNAGATEAREA 0.159000 ;
    PORT
      LAYER met2 ;
        RECT 560.370 996.000 560.650 1000.000 ;
    END
  END imem_data[2]
  PIN imem_data[30]
    DIRECTION INPUT ;
    USE SIGNAL ;
    ANTENNAGATEAREA 0.159000 ;
    PORT
      LAYER met2 ;
        RECT 589.350 996.000 589.630 1000.000 ;
    END
  END imem_data[30]
  PIN imem_data[31]
    DIRECTION INPUT ;
    USE SIGNAL ;
    ANTENNAGATEAREA 0.159000 ;
    PORT
      LAYER met2 ;
        RECT 579.690 996.000 579.970 1000.000 ;
    END
  END imem_data[31]
  PIN imem_data[3]
    DIRECTION INPUT ;
    USE SIGNAL ;
    ANTENNAGATEAREA 0.159000 ;
    PORT
      LAYER met2 ;
        RECT 557.150 996.000 557.430 1000.000 ;
    END
  END imem_data[3]
  PIN imem_data[4]
    DIRECTION INPUT ;
    USE SIGNAL ;
    ANTENNAGATEAREA 0.159000 ;
    PORT
      LAYER met2 ;
        RECT 576.470 996.000 576.750 1000.000 ;
    END
  END imem_data[4]
  PIN imem_data[5]
    DIRECTION INPUT ;
    USE SIGNAL ;
    ANTENNAGATEAREA 0.159000 ;
    PORT
      LAYER met2 ;
        RECT 563.590 996.000 563.870 1000.000 ;
    END
  END imem_data[5]
  PIN imem_data[6]
    DIRECTION INPUT ;
    USE SIGNAL ;
    ANTENNAGATEAREA 0.159000 ;
    PORT
      LAYER met2 ;
        RECT 553.930 996.000 554.210 1000.000 ;
    END
  END imem_data[6]
  PIN imem_data[7]
    DIRECTION INPUT ;
    USE SIGNAL ;
    ANTENNAGATEAREA 0.159000 ;
    PORT
      LAYER met2 ;
        RECT 544.270 996.000 544.550 1000.000 ;
    END
  END imem_data[7]
  PIN imem_data[8]
    DIRECTION INPUT ;
    USE SIGNAL ;
    ANTENNAGATEAREA 0.159000 ;
    PORT
      LAYER met2 ;
        RECT 547.490 996.000 547.770 1000.000 ;
    END
  END imem_data[8]
  PIN imem_data[9]
    DIRECTION INPUT ;
    USE SIGNAL ;
    ANTENNAGATEAREA 0.159000 ;
    PORT
      LAYER met2 ;
        RECT 541.050 996.000 541.330 1000.000 ;
    END
  END imem_data[9]
  PIN rst
    DIRECTION INPUT ;
    USE SIGNAL ;
    ANTENNAGATEAREA 0.247500 ;
    PORT
      LAYER met3 ;
        RECT 996.000 431.840 1000.000 432.440 ;
    END
  END rst
  OBS
      LAYER li1 ;
        RECT 5.520 10.795 994.060 987.445 ;
      LAYER met1 ;
        RECT 5.520 10.640 994.910 987.600 ;
      LAYER met2 ;
        RECT 21.070 995.720 492.470 996.610 ;
        RECT 493.310 995.720 495.690 996.610 ;
        RECT 496.530 995.720 498.910 996.610 ;
        RECT 499.750 995.720 502.130 996.610 ;
        RECT 502.970 995.720 505.350 996.610 ;
        RECT 506.190 995.720 508.570 996.610 ;
        RECT 509.410 995.720 511.790 996.610 ;
        RECT 512.630 995.720 515.010 996.610 ;
        RECT 515.850 995.720 518.230 996.610 ;
        RECT 519.070 995.720 521.450 996.610 ;
        RECT 522.290 995.720 524.670 996.610 ;
        RECT 525.510 995.720 527.890 996.610 ;
        RECT 528.730 995.720 531.110 996.610 ;
        RECT 531.950 995.720 534.330 996.610 ;
        RECT 535.170 995.720 537.550 996.610 ;
        RECT 538.390 995.720 540.770 996.610 ;
        RECT 541.610 995.720 543.990 996.610 ;
        RECT 544.830 995.720 547.210 996.610 ;
        RECT 548.050 995.720 550.430 996.610 ;
        RECT 551.270 995.720 553.650 996.610 ;
        RECT 554.490 995.720 556.870 996.610 ;
        RECT 557.710 995.720 560.090 996.610 ;
        RECT 560.930 995.720 563.310 996.610 ;
        RECT 564.150 995.720 566.530 996.610 ;
        RECT 567.370 995.720 569.750 996.610 ;
        RECT 570.590 995.720 572.970 996.610 ;
        RECT 573.810 995.720 576.190 996.610 ;
        RECT 577.030 995.720 579.410 996.610 ;
        RECT 580.250 995.720 582.630 996.610 ;
        RECT 583.470 995.720 585.850 996.610 ;
        RECT 586.690 995.720 589.070 996.610 ;
        RECT 589.910 995.720 592.290 996.610 ;
        RECT 593.130 995.720 595.510 996.610 ;
        RECT 596.350 995.720 598.730 996.610 ;
        RECT 599.570 995.720 601.950 996.610 ;
        RECT 602.790 995.720 605.170 996.610 ;
        RECT 606.010 995.720 608.390 996.610 ;
        RECT 609.230 995.720 611.610 996.610 ;
        RECT 612.450 995.720 614.830 996.610 ;
        RECT 615.670 995.720 618.050 996.610 ;
        RECT 618.890 995.720 627.710 996.610 ;
        RECT 628.550 995.720 630.930 996.610 ;
        RECT 631.770 995.720 634.150 996.610 ;
        RECT 634.990 995.720 637.370 996.610 ;
        RECT 638.210 995.720 643.810 996.610 ;
        RECT 644.650 995.720 647.030 996.610 ;
        RECT 647.870 995.720 650.250 996.610 ;
        RECT 651.090 995.720 656.690 996.610 ;
        RECT 657.530 995.720 659.910 996.610 ;
        RECT 660.750 995.720 663.130 996.610 ;
        RECT 663.970 995.720 669.570 996.610 ;
        RECT 670.410 995.720 676.010 996.610 ;
        RECT 676.850 995.720 679.230 996.610 ;
        RECT 680.070 995.720 682.450 996.610 ;
        RECT 683.290 995.720 701.770 996.610 ;
        RECT 702.610 995.720 708.210 996.610 ;
        RECT 709.050 995.720 711.430 996.610 ;
        RECT 712.270 995.720 721.090 996.610 ;
        RECT 721.930 995.720 724.310 996.610 ;
        RECT 725.150 995.720 730.750 996.610 ;
        RECT 731.590 995.720 740.410 996.610 ;
        RECT 741.250 995.720 743.630 996.610 ;
        RECT 744.470 995.720 750.070 996.610 ;
        RECT 750.910 995.720 753.290 996.610 ;
        RECT 754.130 995.720 759.730 996.610 ;
        RECT 760.570 995.720 762.950 996.610 ;
        RECT 763.790 995.720 766.170 996.610 ;
        RECT 767.010 995.720 994.890 996.610 ;
        RECT 21.070 4.280 994.890 995.720 ;
        RECT 21.070 4.000 740.410 4.280 ;
        RECT 741.250 4.000 994.890 4.280 ;
      LAYER met3 ;
        RECT 4.000 732.040 996.000 987.525 ;
        RECT 4.400 730.640 996.000 732.040 ;
        RECT 4.000 694.640 996.000 730.640 ;
        RECT 4.000 693.240 995.600 694.640 ;
        RECT 4.000 691.240 996.000 693.240 ;
        RECT 4.000 689.840 995.600 691.240 ;
        RECT 4.000 687.840 996.000 689.840 ;
        RECT 4.000 686.440 995.600 687.840 ;
        RECT 4.000 684.440 996.000 686.440 ;
        RECT 4.000 683.040 995.600 684.440 ;
        RECT 4.000 681.040 996.000 683.040 ;
        RECT 4.000 679.640 995.600 681.040 ;
        RECT 4.000 541.640 996.000 679.640 ;
        RECT 4.000 540.240 995.600 541.640 ;
        RECT 4.000 538.240 996.000 540.240 ;
        RECT 4.000 536.840 995.600 538.240 ;
        RECT 4.000 534.840 996.000 536.840 ;
        RECT 4.000 533.440 995.600 534.840 ;
        RECT 4.000 531.440 996.000 533.440 ;
        RECT 4.000 530.040 995.600 531.440 ;
        RECT 4.000 528.040 996.000 530.040 ;
        RECT 4.000 526.640 995.600 528.040 ;
        RECT 4.000 524.640 996.000 526.640 ;
        RECT 4.000 523.240 995.600 524.640 ;
        RECT 4.000 521.240 996.000 523.240 ;
        RECT 4.000 519.840 995.600 521.240 ;
        RECT 4.000 517.840 996.000 519.840 ;
        RECT 4.000 516.440 995.600 517.840 ;
        RECT 4.000 514.440 996.000 516.440 ;
        RECT 4.000 513.040 995.600 514.440 ;
        RECT 4.000 511.040 996.000 513.040 ;
        RECT 4.000 509.640 995.600 511.040 ;
        RECT 4.000 507.640 996.000 509.640 ;
        RECT 4.000 506.240 995.600 507.640 ;
        RECT 4.000 504.240 996.000 506.240 ;
        RECT 4.000 502.840 995.600 504.240 ;
        RECT 4.000 500.840 996.000 502.840 ;
        RECT 4.000 499.440 995.600 500.840 ;
        RECT 4.000 497.440 996.000 499.440 ;
        RECT 4.000 496.040 995.600 497.440 ;
        RECT 4.000 494.040 996.000 496.040 ;
        RECT 4.000 492.640 995.600 494.040 ;
        RECT 4.000 490.640 996.000 492.640 ;
        RECT 4.000 489.240 995.600 490.640 ;
        RECT 4.000 487.240 996.000 489.240 ;
        RECT 4.000 485.840 995.600 487.240 ;
        RECT 4.000 483.840 996.000 485.840 ;
        RECT 4.000 482.440 995.600 483.840 ;
        RECT 4.000 480.440 996.000 482.440 ;
        RECT 4.000 479.040 995.600 480.440 ;
        RECT 4.000 477.040 996.000 479.040 ;
        RECT 4.000 475.640 995.600 477.040 ;
        RECT 4.000 473.640 996.000 475.640 ;
        RECT 4.000 472.240 995.600 473.640 ;
        RECT 4.000 470.240 996.000 472.240 ;
        RECT 4.000 468.840 995.600 470.240 ;
        RECT 4.000 466.840 996.000 468.840 ;
        RECT 4.000 465.440 995.600 466.840 ;
        RECT 4.000 463.440 996.000 465.440 ;
        RECT 4.000 462.040 995.600 463.440 ;
        RECT 4.000 460.040 996.000 462.040 ;
        RECT 4.000 458.640 995.600 460.040 ;
        RECT 4.000 456.640 996.000 458.640 ;
        RECT 4.000 455.240 995.600 456.640 ;
        RECT 4.000 453.240 996.000 455.240 ;
        RECT 4.000 451.840 995.600 453.240 ;
        RECT 4.000 449.840 996.000 451.840 ;
        RECT 4.000 448.440 995.600 449.840 ;
        RECT 4.000 446.440 996.000 448.440 ;
        RECT 4.000 445.040 995.600 446.440 ;
        RECT 4.000 443.040 996.000 445.040 ;
        RECT 4.000 441.640 995.600 443.040 ;
        RECT 4.000 439.640 996.000 441.640 ;
        RECT 4.000 438.240 995.600 439.640 ;
        RECT 4.000 436.240 996.000 438.240 ;
        RECT 4.000 434.840 995.600 436.240 ;
        RECT 4.000 432.840 996.000 434.840 ;
        RECT 4.000 431.440 995.600 432.840 ;
        RECT 4.000 429.440 996.000 431.440 ;
        RECT 4.000 428.040 995.600 429.440 ;
        RECT 4.000 426.040 996.000 428.040 ;
        RECT 4.000 424.640 995.600 426.040 ;
        RECT 4.000 422.640 996.000 424.640 ;
        RECT 4.000 421.240 995.600 422.640 ;
        RECT 4.000 419.240 996.000 421.240 ;
        RECT 4.000 417.840 995.600 419.240 ;
        RECT 4.000 415.840 996.000 417.840 ;
        RECT 4.000 414.440 995.600 415.840 ;
        RECT 4.000 412.440 996.000 414.440 ;
        RECT 4.000 411.040 995.600 412.440 ;
        RECT 4.000 409.040 996.000 411.040 ;
        RECT 4.000 407.640 995.600 409.040 ;
        RECT 4.000 405.640 996.000 407.640 ;
        RECT 4.000 404.240 995.600 405.640 ;
        RECT 4.000 402.240 996.000 404.240 ;
        RECT 4.000 400.840 995.600 402.240 ;
        RECT 4.000 398.840 996.000 400.840 ;
        RECT 4.000 397.440 995.600 398.840 ;
        RECT 4.000 395.440 996.000 397.440 ;
        RECT 4.000 394.040 995.600 395.440 ;
        RECT 4.000 392.040 996.000 394.040 ;
        RECT 4.000 390.640 995.600 392.040 ;
        RECT 4.000 388.640 996.000 390.640 ;
        RECT 4.000 387.240 995.600 388.640 ;
        RECT 4.000 385.240 996.000 387.240 ;
        RECT 4.000 383.840 995.600 385.240 ;
        RECT 4.000 381.840 996.000 383.840 ;
        RECT 4.000 380.440 995.600 381.840 ;
        RECT 4.000 378.440 996.000 380.440 ;
        RECT 4.000 377.040 995.600 378.440 ;
        RECT 4.000 375.040 996.000 377.040 ;
        RECT 4.000 373.640 995.600 375.040 ;
        RECT 4.000 371.640 996.000 373.640 ;
        RECT 4.000 370.240 995.600 371.640 ;
        RECT 4.000 368.240 996.000 370.240 ;
        RECT 4.000 366.840 995.600 368.240 ;
        RECT 4.000 364.840 996.000 366.840 ;
        RECT 4.000 363.440 995.600 364.840 ;
        RECT 4.000 361.440 996.000 363.440 ;
        RECT 4.000 360.040 995.600 361.440 ;
        RECT 4.000 358.040 996.000 360.040 ;
        RECT 4.000 356.640 995.600 358.040 ;
        RECT 4.000 354.640 996.000 356.640 ;
        RECT 4.000 353.240 995.600 354.640 ;
        RECT 4.000 351.240 996.000 353.240 ;
        RECT 4.000 349.840 995.600 351.240 ;
        RECT 4.000 347.840 996.000 349.840 ;
        RECT 4.000 346.440 995.600 347.840 ;
        RECT 4.000 344.440 996.000 346.440 ;
        RECT 4.000 343.040 995.600 344.440 ;
        RECT 4.000 341.040 996.000 343.040 ;
        RECT 4.000 339.640 995.600 341.040 ;
        RECT 4.000 337.640 996.000 339.640 ;
        RECT 4.000 336.240 995.600 337.640 ;
        RECT 4.000 334.240 996.000 336.240 ;
        RECT 4.000 332.840 995.600 334.240 ;
        RECT 4.000 330.840 996.000 332.840 ;
        RECT 4.000 329.440 995.600 330.840 ;
        RECT 4.000 327.440 996.000 329.440 ;
        RECT 4.000 326.040 995.600 327.440 ;
        RECT 4.000 324.040 996.000 326.040 ;
        RECT 4.000 322.640 995.600 324.040 ;
        RECT 4.000 320.640 996.000 322.640 ;
        RECT 4.000 319.240 995.600 320.640 ;
        RECT 4.000 317.240 996.000 319.240 ;
        RECT 4.000 315.840 995.600 317.240 ;
        RECT 4.000 313.840 996.000 315.840 ;
        RECT 4.000 312.440 995.600 313.840 ;
        RECT 4.000 310.440 996.000 312.440 ;
        RECT 4.000 309.040 995.600 310.440 ;
        RECT 4.000 307.040 996.000 309.040 ;
        RECT 4.000 305.640 995.600 307.040 ;
        RECT 4.000 303.640 996.000 305.640 ;
        RECT 4.000 302.240 995.600 303.640 ;
        RECT 4.000 300.240 996.000 302.240 ;
        RECT 4.000 298.840 995.600 300.240 ;
        RECT 4.000 296.840 996.000 298.840 ;
        RECT 4.000 295.440 995.600 296.840 ;
        RECT 4.000 293.440 996.000 295.440 ;
        RECT 4.000 292.040 995.600 293.440 ;
        RECT 4.000 290.040 996.000 292.040 ;
        RECT 4.000 288.640 995.600 290.040 ;
        RECT 4.000 286.640 996.000 288.640 ;
        RECT 4.000 285.240 995.600 286.640 ;
        RECT 4.000 283.240 996.000 285.240 ;
        RECT 4.000 281.840 995.600 283.240 ;
        RECT 4.000 279.840 996.000 281.840 ;
        RECT 4.000 278.440 995.600 279.840 ;
        RECT 4.000 276.440 996.000 278.440 ;
        RECT 4.000 275.040 995.600 276.440 ;
        RECT 4.000 273.040 996.000 275.040 ;
        RECT 4.000 271.640 995.600 273.040 ;
        RECT 4.000 269.640 996.000 271.640 ;
        RECT 4.000 268.240 995.600 269.640 ;
        RECT 4.000 266.240 996.000 268.240 ;
        RECT 4.000 264.840 995.600 266.240 ;
        RECT 4.000 262.840 996.000 264.840 ;
        RECT 4.000 261.440 995.600 262.840 ;
        RECT 4.000 259.440 996.000 261.440 ;
        RECT 4.000 258.040 995.600 259.440 ;
        RECT 4.000 256.040 996.000 258.040 ;
        RECT 4.000 254.640 995.600 256.040 ;
        RECT 4.000 252.640 996.000 254.640 ;
        RECT 4.000 251.240 995.600 252.640 ;
        RECT 4.000 249.240 996.000 251.240 ;
        RECT 4.000 247.840 995.600 249.240 ;
        RECT 4.000 245.840 996.000 247.840 ;
        RECT 4.000 244.440 995.600 245.840 ;
        RECT 4.000 242.440 996.000 244.440 ;
        RECT 4.000 241.040 995.600 242.440 ;
        RECT 4.000 239.040 996.000 241.040 ;
        RECT 4.000 237.640 995.600 239.040 ;
        RECT 4.000 235.640 996.000 237.640 ;
        RECT 4.000 234.240 995.600 235.640 ;
        RECT 4.000 232.240 996.000 234.240 ;
        RECT 4.000 230.840 995.600 232.240 ;
        RECT 4.000 228.840 996.000 230.840 ;
        RECT 4.000 227.440 995.600 228.840 ;
        RECT 4.000 225.440 996.000 227.440 ;
        RECT 4.000 224.040 995.600 225.440 ;
        RECT 4.000 10.715 996.000 224.040 ;
      LAYER met4 ;
        RECT 164.975 261.975 174.240 980.385 ;
        RECT 176.640 261.975 177.540 980.385 ;
        RECT 179.940 261.975 327.840 980.385 ;
        RECT 330.240 261.975 331.140 980.385 ;
        RECT 333.540 261.975 481.440 980.385 ;
        RECT 483.840 261.975 484.740 980.385 ;
        RECT 487.140 261.975 635.040 980.385 ;
        RECT 637.440 261.975 638.340 980.385 ;
        RECT 640.740 261.975 788.640 980.385 ;
        RECT 791.040 261.975 791.940 980.385 ;
        RECT 794.340 261.975 942.240 980.385 ;
        RECT 944.640 261.975 945.540 980.385 ;
        RECT 947.940 261.975 991.890 980.385 ;
      LAYER met5 ;
        RECT 214.940 492.770 992.100 628.100 ;
        RECT 214.940 388.500 992.100 484.670 ;
  END
END riscv_cpu
END LIBRARY

